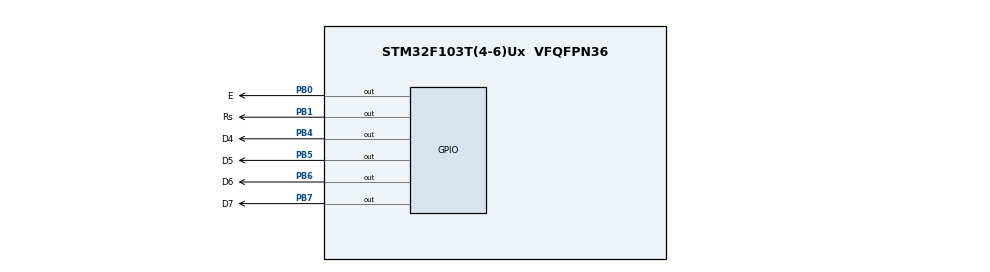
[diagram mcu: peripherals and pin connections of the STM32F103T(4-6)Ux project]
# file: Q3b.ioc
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Mcu.Family=STM32F1
Mcu.Name=STM32F103T(4-6)Ux
Mcu.Package=VFQFPN36
NVIC.PriorityGroup=NVIC_PRIORITYGROUP_4
PB0.GPIO_Label=E
PB0.Signal=GPIO_Output
PB1.GPIO_Label=Rs
PB1.Signal=GPIO_Output
PB4.GPIO_Label=D4
PB4.Signal=GPIO_Output
PB5.GPIO_Label=D5
PB5.Signal=GPIO_Output
PB6.GPIO_Label=D6
PB6.Signal=GPIO_Output
PB7.GPIO_Label=D7
PB7.Signal=GPIO_Output
ProjectManager.HeapSize=0x200
ProjectManager.StackSize=0x400
ProjectManager.TargetToolchain=STM32CubeIDE
RCC.APB1Freq_Value=8000000
RCC.APB2Freq_Value=8000000
board=custom

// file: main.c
/* USER CODE BEGIN Header */
/**
  ******************************************************************************
  * @file           : main.c
  * @brief          : Main program body
  ******************************************************************************
  * @attention
  *
  * Copyright (c) 2023 STMicroelectronics.
  * All rights reserved.
  *
  * This software is licensed under terms that can be found in the LICENSE file
  * in the root directory of this software component.
  * If no LICENSE file comes with this software, it is provided AS-IS.
  *
  ******************************************************************************
  */
#include <stdio.h>
/* USER CODE END Header */
#include "main.h"
#include "lcd.h"

/* USER CODE BEGIN Includes */
	Lcd_HandleTypeDef lcd;
	Lcd_PinType Pins[] = {GPIO_PIN_4,GPIO_PIN_5,GPIO_PIN_6,GPIO_PIN_7};
	Lcd_PortType Ports[] = {GPIOB,GPIOB,GPIOB,GPIOB};

/* USER CODE END Includes */

void SystemClock_Config(void);
static void MX_GPIO_Init(void);

int main(void)
{
  /* USER CODE BEGIN 1 */
	char stra[16];
	char strb[16];
	int a=424;
	float b =a/7.0 ;
  /* USER CODE END 1 */

  /* MCU Configuration--------------------------------------------------------*/

  /* Reset of all peripherals, Initializes the Flash interface and the Systick. */
  HAL_Init();

  /* Configure the system clock */
  SystemClock_Config();

  /* Initialize all configured peripherals */
  MX_GPIO_Init();
  /* USER CODE BEGIN 2 */
  lcd = Lcd_create(Ports, Pins, GPIOB, GPIO_PIN_1, GPIOB, GPIO_PIN_0, LCD_4_BIT_MODE);

  /* USER CODE END 2 */

  /* Infinite loop */
  /* USER CODE BEGIN WHILE */
  while (1)
  {
	  sprintf(stra, "a: %d", a);
	  sprintf(strb, "b: %.4f", b);
	  Lcd_cursor(&lcd, 0, 0);
	  Lcd_string(&lcd, stra);
	  Lcd_cursor(&lcd, 1, 0);
	  Lcd_string(&lcd, strb);

    /* USER CODE END WHILE */

  }
}

void SystemClock_Config(void)
{
  RCC_OscInitTypeDef RCC_OscInitStruct = {0};
  RCC_ClkInitTypeDef RCC_ClkInitStruct = {0};

  /** Initializes the RCC Oscillators according to the specified parameters
  * in the RCC_OscInitTypeDef structure.
  */
  RCC_OscInitStruct.OscillatorType = RCC_OSCILLATORTYPE_HSI;
  RCC_OscInitStruct.HSIState = RCC_HSI_ON;
  RCC_OscInitStruct.HSICalibrationValue = RCC_HSICALIBRATION_DEFAULT;
  RCC_OscInitStruct.PLL.PLLState = RCC_PLL_ON;
  RCC_OscInitStruct.PLL.PLLSource = RCC_PLLSOURCE_HSI_DIV2;
  RCC_OscInitStruct.PLL.PLLMUL = RCC_PLL_MUL5;
  if (HAL_RCC_OscConfig(&RCC_OscInitStruct) != HAL_OK)
  {
    Error_Handler();
  }

  /** Initializes the CPU, AHB and APB buses clocks
  */
  RCC_ClkInitStruct.ClockType = RCC_CLOCKTYPE_HCLK|RCC_CLOCKTYPE_SYSCLK
                              |RCC_CLOCKTYPE_PCLK1|RCC_CLOCKTYPE_PCLK2;
  RCC_ClkInitStruct.SYSCLKSource = RCC_SYSCLKSOURCE_PLLCLK;
  RCC_ClkInitStruct.AHBCLKDivider = RCC_SYSCLK_DIV1;
  RCC_ClkInitStruct.APB1CLKDivider = RCC_HCLK_DIV1;
  RCC_ClkInitStruct.APB2CLKDivider = RCC_HCLK_DIV1;

  if (HAL_RCC_ClockConfig(&RCC_ClkInitStruct, FLASH_LATENCY_0) != HAL_OK)
  {
    Error_Handler();
  }
}

static void MX_GPIO_Init(void)
{
  GPIO_InitTypeDef GPIO_InitStruct = {0};

  /* GPIO Ports Clock Enable */
  __HAL_RCC_GPIOB_CLK_ENABLE();

  /*Configure GPIO pin Output Level */
  HAL_GPIO_WritePin(GPIOB, E_Pin|Rs_Pin|D4_Pin|D5_Pin
                          |D6_Pin|D7_Pin, GPIO_PIN_RESET);

  /*Configure GPIO pins : E_Pin Rs_Pin D4_Pin D5_Pin
                           D6_Pin D7_Pin */
  GPIO_InitStruct.Pin = E_Pin|Rs_Pin|D4_Pin|D5_Pin
                          |D6_Pin|D7_Pin;
  GPIO_InitStruct.Mode = GPIO_MODE_OUTPUT_PP;
  GPIO_InitStruct.Pull = GPIO_NOPULL;
  GPIO_InitStruct.Speed = GPIO_SPEED_FREQ_LOW;
  HAL_GPIO_Init(GPIOB, &GPIO_InitStruct);

}

void Error_Handler(void)
{
  __disable_irq();
  while (1)
  {
  }
}
